VERSION 5.7 ;
BUSBITCHARS "[]" ;
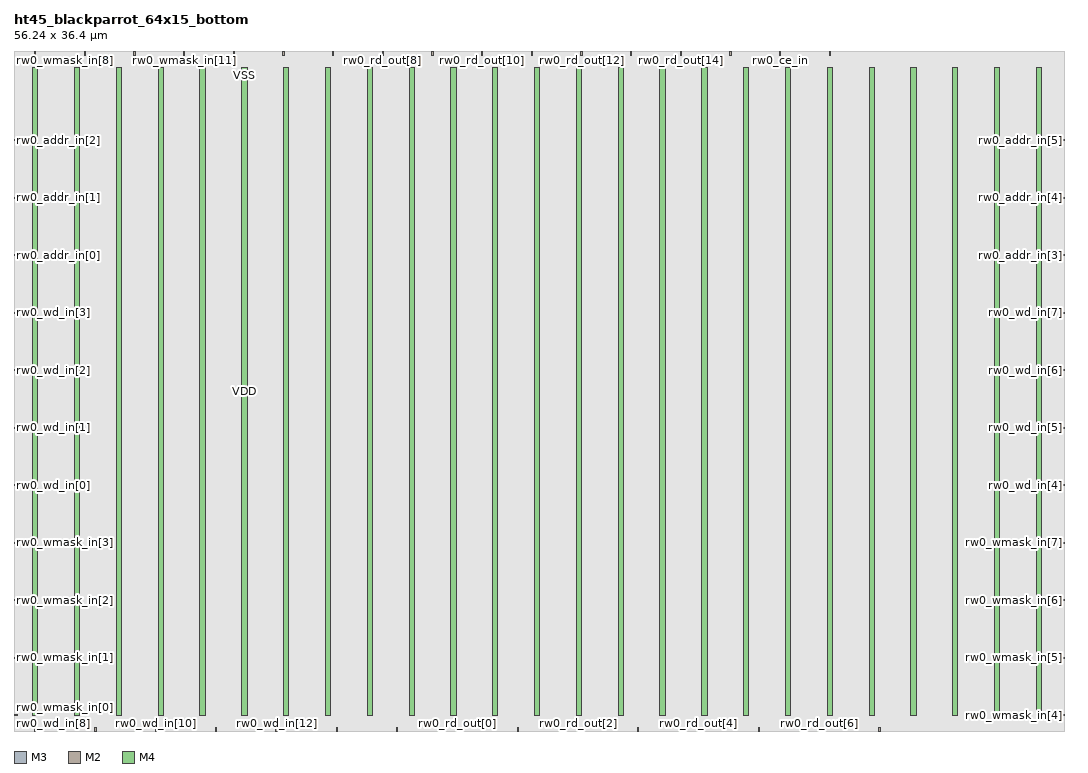
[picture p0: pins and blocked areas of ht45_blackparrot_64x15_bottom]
MACRO ht45_blackparrot_64x15_bottom
  FOREIGN ht45_blackparrot_64x15_bottom 0 0 ;
  SYMMETRY X Y R90 ;
  SIZE 56.240 BY 36.400 ;
  CLASS BLOCK ;
  PIN rw0_wmask_in[0]
    DIRECTION INPUT ;
    USE SIGNAL ;
    SHAPE ABUTMENT ;
    PORT
      LAYER M3 ;
      RECT 0.000 0.805 0.210 0.875 ;
    END
  END rw0_wmask_in[0]
  PIN rw0_wmask_in[1]
    DIRECTION INPUT ;
    USE SIGNAL ;
    SHAPE ABUTMENT ;
    PORT
      LAYER M3 ;
      RECT 0.000 3.885 0.210 3.955 ;
    END
  END rw0_wmask_in[1]
  PIN rw0_wmask_in[2]
    DIRECTION INPUT ;
    USE SIGNAL ;
    SHAPE ABUTMENT ;
    PORT
      LAYER M3 ;
      RECT 0.000 6.965 0.210 7.035 ;
    END
  END rw0_wmask_in[2]
  PIN rw0_wmask_in[3]
    DIRECTION INPUT ;
    USE SIGNAL ;
    SHAPE ABUTMENT ;
    PORT
      LAYER M3 ;
      RECT 0.000 10.045 0.210 10.115 ;
    END
  END rw0_wmask_in[3]
  PIN rw0_wmask_in[4]
    DIRECTION INPUT ;
    USE SIGNAL ;
    SHAPE ABUTMENT ;
    PORT
      LAYER M3 ;
      RECT 56.030 0.805 56.240 0.875 ;
    END
  END rw0_wmask_in[4]
  PIN rw0_wmask_in[5]
    DIRECTION INPUT ;
    USE SIGNAL ;
    SHAPE ABUTMENT ;
    PORT
      LAYER M3 ;
      RECT 56.030 3.885 56.240 3.955 ;
    END
  END rw0_wmask_in[5]
  PIN rw0_wmask_in[6]
    DIRECTION INPUT ;
    USE SIGNAL ;
    SHAPE ABUTMENT ;
    PORT
      LAYER M3 ;
      RECT 56.030 6.965 56.240 7.035 ;
    END
  END rw0_wmask_in[6]
  PIN rw0_wmask_in[7]
    DIRECTION INPUT ;
    USE SIGNAL ;
    SHAPE ABUTMENT ;
    PORT
      LAYER M3 ;
      RECT 56.030 10.045 56.240 10.115 ;
    END
  END rw0_wmask_in[7]
  PIN rw0_wmask_in[8]
    DIRECTION INPUT ;
    USE SIGNAL ;
    SHAPE ABUTMENT ;
    PORT
      LAYER M2 ;
      RECT 1.105 36.190 1.175 36.400 ;
    END
  END rw0_wmask_in[8]
  PIN rw0_wmask_in[9]
    DIRECTION INPUT ;
    USE SIGNAL ;
    SHAPE ABUTMENT ;
    PORT
      LAYER M2 ;
      RECT 3.765 36.190 3.835 36.400 ;
    END
  END rw0_wmask_in[9]
  PIN rw0_wmask_in[10]
    DIRECTION INPUT ;
    USE SIGNAL ;
    SHAPE ABUTMENT ;
    PORT
      LAYER M2 ;
      RECT 6.425 36.190 6.495 36.400 ;
    END
  END rw0_wmask_in[10]
  PIN rw0_wmask_in[11]
    DIRECTION INPUT ;
    USE SIGNAL ;
    SHAPE ABUTMENT ;
    PORT
      LAYER M2 ;
      RECT 9.085 36.190 9.155 36.400 ;
    END
  END rw0_wmask_in[11]
  PIN rw0_wmask_in[12]
    DIRECTION INPUT ;
    USE SIGNAL ;
    SHAPE ABUTMENT ;
    PORT
      LAYER M2 ;
      RECT 11.745 36.190 11.815 36.400 ;
    END
  END rw0_wmask_in[12]
  PIN rw0_wmask_in[13]
    DIRECTION INPUT ;
    USE SIGNAL ;
    SHAPE ABUTMENT ;
    PORT
      LAYER M2 ;
      RECT 14.405 36.190 14.475 36.400 ;
    END
  END rw0_wmask_in[13]
  PIN rw0_wmask_in[14]
    DIRECTION INPUT ;
    USE SIGNAL ;
    SHAPE ABUTMENT ;
    PORT
      LAYER M2 ;
      RECT 17.065 36.190 17.135 36.400 ;
    END
  END rw0_wmask_in[14]
  PIN rw0_wd_in[0]
    DIRECTION INPUT ;
    USE SIGNAL ;
    SHAPE ABUTMENT ;
    PORT
      LAYER M3 ;
      RECT 0.000 13.125 0.210 13.195 ;
    END
  END rw0_wd_in[0]
  PIN rw0_wd_in[1]
    DIRECTION INPUT ;
    USE SIGNAL ;
    SHAPE ABUTMENT ;
    PORT
      LAYER M3 ;
      RECT 0.000 16.205 0.210 16.275 ;
    END
  END rw0_wd_in[1]
  PIN rw0_wd_in[2]
    DIRECTION INPUT ;
    USE SIGNAL ;
    SHAPE ABUTMENT ;
    PORT
      LAYER M3 ;
      RECT 0.000 19.285 0.210 19.355 ;
    END
  END rw0_wd_in[2]
  PIN rw0_wd_in[3]
    DIRECTION INPUT ;
    USE SIGNAL ;
    SHAPE ABUTMENT ;
    PORT
      LAYER M3 ;
      RECT 0.000 22.365 0.210 22.435 ;
    END
  END rw0_wd_in[3]
  PIN rw0_wd_in[4]
    DIRECTION INPUT ;
    USE SIGNAL ;
    SHAPE ABUTMENT ;
    PORT
      LAYER M3 ;
      RECT 56.030 13.125 56.240 13.195 ;
    END
  END rw0_wd_in[4]
  PIN rw0_wd_in[5]
    DIRECTION INPUT ;
    USE SIGNAL ;
    SHAPE ABUTMENT ;
    PORT
      LAYER M3 ;
      RECT 56.030 16.205 56.240 16.275 ;
    END
  END rw0_wd_in[5]
  PIN rw0_wd_in[6]
    DIRECTION INPUT ;
    USE SIGNAL ;
    SHAPE ABUTMENT ;
    PORT
      LAYER M3 ;
      RECT 56.030 19.285 56.240 19.355 ;
    END
  END rw0_wd_in[6]
  PIN rw0_wd_in[7]
    DIRECTION INPUT ;
    USE SIGNAL ;
    SHAPE ABUTMENT ;
    PORT
      LAYER M3 ;
      RECT 56.030 22.365 56.240 22.435 ;
    END
  END rw0_wd_in[7]
  PIN rw0_wd_in[8]
    DIRECTION INPUT ;
    USE SIGNAL ;
    SHAPE ABUTMENT ;
    PORT
      LAYER M2 ;
      RECT 1.105 0.000 1.175 0.210 ;
    END
  END rw0_wd_in[8]
  PIN rw0_wd_in[9]
    DIRECTION INPUT ;
    USE SIGNAL ;
    SHAPE ABUTMENT ;
    PORT
      LAYER M2 ;
      RECT 4.335 0.000 4.405 0.210 ;
    END
  END rw0_wd_in[9]
  PIN rw0_wd_in[10]
    DIRECTION INPUT ;
    USE SIGNAL ;
    SHAPE ABUTMENT ;
    PORT
      LAYER M2 ;
      RECT 7.565 0.000 7.635 0.210 ;
    END
  END rw0_wd_in[10]
  PIN rw0_wd_in[11]
    DIRECTION INPUT ;
    USE SIGNAL ;
    SHAPE ABUTMENT ;
    PORT
      LAYER M2 ;
      RECT 10.795 0.000 10.865 0.210 ;
    END
  END rw0_wd_in[11]
  PIN rw0_wd_in[12]
    DIRECTION INPUT ;
    USE SIGNAL ;
    SHAPE ABUTMENT ;
    PORT
      LAYER M2 ;
      RECT 14.025 0.000 14.095 0.210 ;
    END
  END rw0_wd_in[12]
  PIN rw0_wd_in[13]
    DIRECTION INPUT ;
    USE SIGNAL ;
    SHAPE ABUTMENT ;
    PORT
      LAYER M2 ;
      RECT 17.255 0.000 17.325 0.210 ;
    END
  END rw0_wd_in[13]
  PIN rw0_wd_in[14]
    DIRECTION INPUT ;
    USE SIGNAL ;
    SHAPE ABUTMENT ;
    PORT
      LAYER M2 ;
      RECT 20.485 0.000 20.555 0.210 ;
    END
  END rw0_wd_in[14]
  PIN rw0_rd_out[0]
    DIRECTION OUTPUT ;
    USE SIGNAL ;
    SHAPE ABUTMENT ;
    PORT
      LAYER M2 ;
      RECT 23.715 0.000 23.785 0.210 ;
    END
  END rw0_rd_out[0]
  PIN rw0_rd_out[1]
    DIRECTION OUTPUT ;
    USE SIGNAL ;
    SHAPE ABUTMENT ;
    PORT
      LAYER M2 ;
      RECT 26.945 0.000 27.015 0.210 ;
    END
  END rw0_rd_out[1]
  PIN rw0_rd_out[2]
    DIRECTION OUTPUT ;
    USE SIGNAL ;
    SHAPE ABUTMENT ;
    PORT
      LAYER M2 ;
      RECT 30.175 0.000 30.245 0.210 ;
    END
  END rw0_rd_out[2]
  PIN rw0_rd_out[3]
    DIRECTION OUTPUT ;
    USE SIGNAL ;
    SHAPE ABUTMENT ;
    PORT
      LAYER M2 ;
      RECT 33.405 0.000 33.475 0.210 ;
    END
  END rw0_rd_out[3]
  PIN rw0_rd_out[4]
    DIRECTION OUTPUT ;
    USE SIGNAL ;
    SHAPE ABUTMENT ;
    PORT
      LAYER M2 ;
      RECT 36.635 0.000 36.705 0.210 ;
    END
  END rw0_rd_out[4]
  PIN rw0_rd_out[5]
    DIRECTION OUTPUT ;
    USE SIGNAL ;
    SHAPE ABUTMENT ;
    PORT
      LAYER M2 ;
      RECT 39.865 0.000 39.935 0.210 ;
    END
  END rw0_rd_out[5]
  PIN rw0_rd_out[6]
    DIRECTION OUTPUT ;
    USE SIGNAL ;
    SHAPE ABUTMENT ;
    PORT
      LAYER M2 ;
      RECT 43.095 0.000 43.165 0.210 ;
    END
  END rw0_rd_out[6]
  PIN rw0_rd_out[7]
    DIRECTION OUTPUT ;
    USE SIGNAL ;
    SHAPE ABUTMENT ;
    PORT
      LAYER M2 ;
      RECT 46.325 0.000 46.395 0.210 ;
    END
  END rw0_rd_out[7]
  PIN rw0_rd_out[8]
    DIRECTION OUTPUT ;
    USE SIGNAL ;
    SHAPE ABUTMENT ;
    PORT
      LAYER M2 ;
      RECT 19.725 36.190 19.795 36.400 ;
    END
  END rw0_rd_out[8]
  PIN rw0_rd_out[9]
    DIRECTION OUTPUT ;
    USE SIGNAL ;
    SHAPE ABUTMENT ;
    PORT
      LAYER M2 ;
      RECT 22.385 36.190 22.455 36.400 ;
    END
  END rw0_rd_out[9]
  PIN rw0_rd_out[10]
    DIRECTION OUTPUT ;
    USE SIGNAL ;
    SHAPE ABUTMENT ;
    PORT
      LAYER M2 ;
      RECT 25.045 36.190 25.115 36.400 ;
    END
  END rw0_rd_out[10]
  PIN rw0_rd_out[11]
    DIRECTION OUTPUT ;
    USE SIGNAL ;
    SHAPE ABUTMENT ;
    PORT
      LAYER M2 ;
      RECT 27.705 36.190 27.775 36.400 ;
    END
  END rw0_rd_out[11]
  PIN rw0_rd_out[12]
    DIRECTION OUTPUT ;
    USE SIGNAL ;
    SHAPE ABUTMENT ;
    PORT
      LAYER M2 ;
      RECT 30.365 36.190 30.435 36.400 ;
    END
  END rw0_rd_out[12]
  PIN rw0_rd_out[13]
    DIRECTION OUTPUT ;
    USE SIGNAL ;
    SHAPE ABUTMENT ;
    PORT
      LAYER M2 ;
      RECT 33.025 36.190 33.095 36.400 ;
    END
  END rw0_rd_out[13]
  PIN rw0_rd_out[14]
    DIRECTION OUTPUT ;
    USE SIGNAL ;
    SHAPE ABUTMENT ;
    PORT
      LAYER M2 ;
      RECT 35.685 36.190 35.755 36.400 ;
    END
  END rw0_rd_out[14]
  PIN rw0_addr_in[0]
    DIRECTION INPUT ;
    USE SIGNAL ;
    SHAPE ABUTMENT ;
    PORT
      LAYER M3 ;
      RECT 0.000 25.445 0.210 25.515 ;
    END
  END rw0_addr_in[0]
  PIN rw0_addr_in[1]
    DIRECTION INPUT ;
    USE SIGNAL ;
    SHAPE ABUTMENT ;
    PORT
      LAYER M3 ;
      RECT 0.000 28.525 0.210 28.595 ;
    END
  END rw0_addr_in[1]
  PIN rw0_addr_in[2]
    DIRECTION INPUT ;
    USE SIGNAL ;
    SHAPE ABUTMENT ;
    PORT
      LAYER M3 ;
      RECT 0.000 31.605 0.210 31.675 ;
    END
  END rw0_addr_in[2]
  PIN rw0_addr_in[3]
    DIRECTION INPUT ;
    USE SIGNAL ;
    SHAPE ABUTMENT ;
    PORT
      LAYER M3 ;
      RECT 56.030 25.445 56.240 25.515 ;
    END
  END rw0_addr_in[3]
  PIN rw0_addr_in[4]
    DIRECTION INPUT ;
    USE SIGNAL ;
    SHAPE ABUTMENT ;
    PORT
      LAYER M3 ;
      RECT 56.030 28.525 56.240 28.595 ;
    END
  END rw0_addr_in[4]
  PIN rw0_addr_in[5]
    DIRECTION INPUT ;
    USE SIGNAL ;
    SHAPE ABUTMENT ;
    PORT
      LAYER M3 ;
      RECT 56.030 31.605 56.240 31.675 ;
    END
  END rw0_addr_in[5]
  PIN rw0_we_in
    DIRECTION INPUT ;
    USE SIGNAL ;
    SHAPE ABUTMENT ;
    PORT
      LAYER M2 ;
      RECT 38.345 36.190 38.415 36.400 ;
    END
  END rw0_we_in
  PIN rw0_ce_in
    DIRECTION INPUT ;
    USE SIGNAL ;
    SHAPE ABUTMENT ;
    PORT
      LAYER M2 ;
      RECT 41.005 36.190 41.075 36.400 ;
    END
  END rw0_ce_in
  PIN rw0_clk
    DIRECTION INPUT ;
    USE SIGNAL ;
    SHAPE ABUTMENT ;
    PORT
      LAYER M2 ;
      RECT 43.665 36.190 43.735 36.400 ;
    END
  END rw0_clk
  PIN VSS
    DIRECTION INOUT ;
    USE GROUND ;
    PORT
      LAYER M4 ;
      RECT 1.000 0.840 1.280 35.560 ;
      RECT 3.240 0.840 3.520 35.560 ;
      RECT 5.480 0.840 5.760 35.560 ;
      RECT 7.720 0.840 8.000 35.560 ;
      RECT 9.960 0.840 10.240 35.560 ;
      RECT 12.200 0.840 12.480 35.560 ;
      RECT 14.440 0.840 14.720 35.560 ;
      RECT 16.680 0.840 16.960 35.560 ;
      RECT 18.920 0.840 19.200 35.560 ;
      RECT 21.160 0.840 21.440 35.560 ;
      RECT 23.400 0.840 23.680 35.560 ;
      RECT 25.640 0.840 25.920 35.560 ;
      RECT 27.880 0.840 28.160 35.560 ;
      RECT 30.120 0.840 30.400 35.560 ;
      RECT 32.360 0.840 32.640 35.560 ;
      RECT 34.600 0.840 34.880 35.560 ;
      RECT 36.840 0.840 37.120 35.560 ;
      RECT 39.080 0.840 39.360 35.560 ;
      RECT 41.320 0.840 41.600 35.560 ;
      RECT 43.560 0.840 43.840 35.560 ;
      RECT 45.800 0.840 46.080 35.560 ;
      RECT 48.040 0.840 48.320 35.560 ;
      RECT 50.280 0.840 50.560 35.560 ;
      RECT 52.520 0.840 52.800 35.560 ;
      RECT 54.760 0.840 55.040 35.560 ;
    END
  END VSS
  PIN VDD
    DIRECTION INOUT ;
    USE POWER ;
    PORT
      LAYER M4 ;
      RECT 1.000 0.840 1.280 35.560 ;
      RECT 3.240 0.840 3.520 35.560 ;
      RECT 5.480 0.840 5.760 35.560 ;
      RECT 7.720 0.840 8.000 35.560 ;
      RECT 9.960 0.840 10.240 35.560 ;
      RECT 12.200 0.840 12.480 35.560 ;
      RECT 14.440 0.840 14.720 35.560 ;
      RECT 16.680 0.840 16.960 35.560 ;
      RECT 18.920 0.840 19.200 35.560 ;
      RECT 21.160 0.840 21.440 35.560 ;
      RECT 23.400 0.840 23.680 35.560 ;
      RECT 25.640 0.840 25.920 35.560 ;
      RECT 27.880 0.840 28.160 35.560 ;
      RECT 30.120 0.840 30.400 35.560 ;
      RECT 32.360 0.840 32.640 35.560 ;
      RECT 34.600 0.840 34.880 35.560 ;
      RECT 36.840 0.840 37.120 35.560 ;
      RECT 39.080 0.840 39.360 35.560 ;
      RECT 41.320 0.840 41.600 35.560 ;
      RECT 43.560 0.840 43.840 35.560 ;
      RECT 45.800 0.840 46.080 35.560 ;
      RECT 48.040 0.840 48.320 35.560 ;
      RECT 50.280 0.840 50.560 35.560 ;
      RECT 52.520 0.840 52.800 35.560 ;
      RECT 54.760 0.840 55.040 35.560 ;
    END
  END VDD
  OBS
    LAYER M1 ;
    RECT 0 0 56.240 36.400 ;
    LAYER M2 ;
    RECT 0 0 56.240 36.400 ;
    LAYER M3 ;
    RECT 0 0 56.240 36.400 ;
    LAYER M4 ;
    RECT 0 0 56.240 36.400 ;
    LAYER OVERLAP ;
    RECT 0 0 56.240 36.400 ;
  END
END ht45_blackparrot_64x15_bottom

END LIBRARY
